VERSION 5.8 ;
BUSBITCHARS "[]" ;
DIVIDERCHAR "/" ;
UNITS
    DATABASE MICRONS 1000 ;
END UNITS

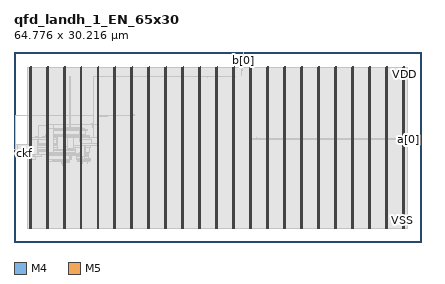
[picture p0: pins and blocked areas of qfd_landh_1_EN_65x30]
MACRO qfd_landh_1_EN_65x30
  FOREIGN qfd_landh_1_EN_65x30 0 0 ;
  CLASS BLOCK ;
  SIZE 64.776 BY 30.216 ;
  PIN a[0]
    DIRECTION INPUT ;
    USE SIGNAL ;
    PORT
      LAYER M4 ;
        RECT  64.692 16.272 64.776 16.296 ;
    END
  END a[0]
  PIN b[0]
    DIRECTION OUTPUT ;
    USE SIGNAL ;
    PORT
      LAYER M5 ;
        RECT  36.432 30.132 36.456 30.216 ;
    END
  END b[0]
  PIN ck
    DIRECTION INPUT ;
    USE SIGNAL ;
    PORT
      LAYER M4 ;
        RECT  0 13.968 0.084 13.992 ;
    END
  END ck
  PIN ckf
    DIRECTION INPUT ;
    USE SIGNAL ;
    PORT
      LAYER M4 ;
        RECT  0 14.064 0.084 14.088 ;
    END
  END ckf
  PIN ea
    DIRECTION INPUT ;
    USE SIGNAL ;
    PORT
      LAYER M4 ;
        RECT  64.692 16.368 64.776 16.392 ;
    END
  END ea
  PIN fault
    DIRECTION OUTPUT ;
    USE SIGNAL ;
    PORT
      LAYER M4 ;
        RECT  0 14.16 0.084 14.184 ;
    END
  END fault
  PIN k0
    DIRECTION INPUT ;
    USE SIGNAL ;
    PORT
      LAYER M4 ;
        RECT  0 14.256 0.084 14.28 ;
    END
  END k0
  PIN k1
    DIRECTION INPUT ;
    USE SIGNAL ;
    PORT
      LAYER M4 ;
        RECT  0 14.352 0.084 14.376 ;
    END
  END k1
  PIN k2
    DIRECTION INPUT ;
    USE SIGNAL ;
    PORT
      LAYER M4 ;
        RECT  0 14.448 0.084 14.472 ;
    END
  END k2
  PIN rs
    DIRECTION INPUT ;
    USE SIGNAL ;
    PORT
      LAYER M4 ;
        RECT  0 14.544 0.084 14.568 ;
    END
  END rs
  PIN tie_hi
    DIRECTION OUTPUT ;
    USE SIGNAL ;
    PORT
      LAYER M4 ;
        RECT  0 14.64 0.084 14.664 ;
    END
  END tie_hi
  PIN tie_lo
    DIRECTION OUTPUT ;
    USE SIGNAL ;
    PORT
      LAYER M4 ;
        RECT  0 14.736 0.084 14.76 ;
    END
  END tie_lo
  PIN VDD
    DIRECTION INOUT ;
    USE POWER ;
    PORT
      LAYER M5 ;
        RECT  61.992 2.151 62.112 27.833 ;
        RECT  59.292 2.151 59.412 27.833 ;
        RECT  56.592 2.151 56.712 27.833 ;
        RECT  53.892 2.151 54.012 27.833 ;
        RECT  51.192 2.151 51.312 27.833 ;
        RECT  48.492 2.151 48.612 27.833 ;
        RECT  45.792 2.151 45.912 27.833 ;
        RECT  43.092 2.151 43.212 27.833 ;
        RECT  40.392 2.151 40.512 27.833 ;
        RECT  37.692 2.151 37.812 27.833 ;
        RECT  34.992 2.151 35.112 27.833 ;
        RECT  32.292 2.151 32.412 27.833 ;
        RECT  29.592 2.151 29.712 27.833 ;
        RECT  26.892 2.151 27.012 27.833 ;
        RECT  24.192 2.151 24.312 27.833 ;
        RECT  21.492 2.151 21.612 27.833 ;
        RECT  18.792 2.151 18.912 27.833 ;
        RECT  16.092 2.151 16.212 27.833 ;
        RECT  13.392 2.151 13.512 27.833 ;
        RECT  10.692 2.151 10.812 27.833 ;
        RECT  7.992 2.151 8.112 27.833 ;
        RECT  5.292 2.151 5.412 27.833 ;
        RECT  2.592 2.151 2.712 27.833 ;
    END
  END VDD
  PIN VSS
    DIRECTION INOUT ;
    USE GROUND ;
    PORT
      LAYER M5 ;
        RECT  61.8 2.137 61.92 27.819 ;
        RECT  59.1 2.137 59.22 27.819 ;
        RECT  56.4 2.137 56.52 27.819 ;
        RECT  53.7 2.137 53.82 27.819 ;
        RECT  51 2.137 51.12 27.819 ;
        RECT  48.3 2.137 48.42 27.819 ;
        RECT  45.6 2.137 45.72 27.819 ;
        RECT  42.9 2.137 43.02 27.819 ;
        RECT  40.2 2.137 40.32 27.819 ;
        RECT  37.5 2.137 37.62 27.819 ;
        RECT  34.8 2.137 34.92 27.819 ;
        RECT  32.1 2.137 32.22 27.819 ;
        RECT  29.4 2.137 29.52 27.819 ;
        RECT  26.7 2.137 26.82 27.819 ;
        RECT  24 2.137 24.12 27.819 ;
        RECT  21.3 2.137 21.42 27.819 ;
        RECT  18.6 2.137 18.72 27.819 ;
        RECT  15.9 2.137 16.02 27.819 ;
        RECT  13.2 2.137 13.32 27.819 ;
        RECT  10.5 2.137 10.62 27.819 ;
        RECT  7.8 2.137 7.92 27.819 ;
        RECT  5.1 2.137 5.22 27.819 ;
        RECT  2.4 2.137 2.52 27.819 ;
    END
  END VSS
  OBS
    LAYER RVTN ;
     RECT  2.16 2.16 62.586 2.295 ;
     RECT  2.16 2.565 62.586 2.835 ;
     RECT  2.16 3.105 62.586 3.375 ;
     RECT  2.16 3.645 62.586 3.915 ;
     RECT  2.16 4.185 62.586 4.455 ;
     RECT  2.16 4.725 62.586 4.995 ;
     RECT  2.16 5.265 62.586 5.535 ;
     RECT  2.16 5.805 62.586 6.075 ;
     RECT  2.16 6.345 62.586 6.615 ;
     RECT  2.16 6.885 62.586 7.155 ;
     RECT  2.16 7.425 62.586 7.695 ;
     RECT  2.16 7.965 62.586 8.235 ;
     RECT  2.16 8.505 62.586 8.775 ;
     RECT  2.16 9.045 62.586 9.315 ;
     RECT  2.16 9.585 62.586 9.855 ;
     RECT  2.16 10.125 62.586 10.395 ;
     RECT  2.16 10.665 62.586 10.935 ;
     RECT  2.16 11.205 62.586 11.475 ;
     RECT  2.16 11.745 62.586 12.015 ;
     RECT  2.16 12.285 62.586 12.555 ;
     RECT  2.16 12.825 62.586 13.095 ;
     RECT  2.16 13.365 62.586 13.635 ;
     RECT  2.16 13.905 62.586 14.175 ;
     RECT  2.16 14.445 62.586 14.715 ;
     RECT  2.16 14.985 62.586 15.255 ;
     RECT  2.16 15.525 62.586 15.795 ;
     RECT  2.16 16.065 62.586 16.335 ;
     RECT  2.16 16.605 62.586 16.875 ;
     RECT  2.16 17.145 62.586 17.415 ;
     RECT  2.16 17.685 62.586 17.955 ;
     RECT  2.16 18.225 62.586 18.495 ;
     RECT  2.16 18.765 62.586 19.035 ;
     RECT  2.16 19.305 62.586 19.575 ;
     RECT  2.16 19.845 62.586 20.115 ;
     RECT  2.16 20.385 62.586 20.655 ;
     RECT  2.16 20.925 62.586 21.195 ;
     RECT  2.16 21.465 62.586 21.735 ;
     RECT  2.16 22.005 62.586 22.275 ;
     RECT  2.16 22.545 62.586 22.815 ;
     RECT  2.16 23.085 62.586 23.355 ;
     RECT  2.16 23.625 62.586 23.895 ;
     RECT  2.16 24.165 62.586 24.435 ;
     RECT  2.16 24.705 62.586 24.975 ;
     RECT  2.16 25.245 62.586 25.515 ;
     RECT  2.16 25.785 62.586 26.055 ;
     RECT  2.16 26.325 62.586 26.595 ;
     RECT  2.16 26.865 62.586 27.135 ;
     RECT  2.16 27.405 62.586 27.675 ;
    LAYER RVTP ;
     RECT  2.16 2.295 62.586 2.565 ;
     RECT  2.16 2.835 62.586 3.105 ;
     RECT  2.16 3.375 62.586 3.645 ;
     RECT  2.16 3.915 62.586 4.185 ;
     RECT  2.16 4.455 62.586 4.725 ;
     RECT  2.16 4.995 62.586 5.265 ;
     RECT  2.16 5.535 62.586 5.805 ;
     RECT  2.16 6.075 62.586 6.345 ;
     RECT  2.16 6.615 62.586 6.885 ;
     RECT  2.16 7.155 62.586 7.425 ;
     RECT  2.16 7.695 62.586 7.965 ;
     RECT  2.16 8.235 62.586 8.505 ;
     RECT  2.16 8.775 62.586 9.045 ;
     RECT  2.16 9.315 62.586 9.585 ;
     RECT  2.16 9.855 62.586 10.125 ;
     RECT  2.16 10.395 62.586 10.665 ;
     RECT  2.16 10.935 62.586 11.205 ;
     RECT  2.16 11.475 62.586 11.745 ;
     RECT  2.16 12.015 62.586 12.285 ;
     RECT  2.16 12.555 62.586 12.825 ;
     RECT  2.16 13.095 62.586 13.365 ;
     RECT  2.16 13.635 62.586 13.905 ;
     RECT  2.16 14.175 62.586 14.445 ;
     RECT  2.16 14.715 62.586 14.985 ;
     RECT  2.16 15.255 62.586 15.525 ;
     RECT  2.16 15.795 62.586 16.065 ;
     RECT  2.16 16.335 62.586 16.605 ;
     RECT  2.16 16.875 62.586 17.145 ;
     RECT  2.16 17.415 62.586 17.685 ;
     RECT  2.16 17.955 62.586 18.225 ;
     RECT  2.16 18.495 62.586 18.765 ;
     RECT  2.16 19.035 62.586 19.305 ;
     RECT  2.16 19.575 62.586 19.845 ;
     RECT  2.16 20.115 62.586 20.385 ;
     RECT  2.16 20.655 62.586 20.925 ;
     RECT  2.16 21.195 62.586 21.465 ;
     RECT  2.16 21.735 62.586 22.005 ;
     RECT  2.16 22.275 62.586 22.545 ;
     RECT  2.16 22.815 62.586 23.085 ;
     RECT  2.16 23.355 62.586 23.625 ;
     RECT  2.16 23.895 62.586 24.165 ;
     RECT  2.16 24.435 62.586 24.705 ;
     RECT  2.16 24.975 62.586 25.245 ;
     RECT  2.16 25.515 62.586 25.785 ;
     RECT  2.16 26.055 62.586 26.325 ;
     RECT  2.16 26.595 62.586 26.865 ;
     RECT  2.16 27.135 62.586 27.405 ;
     RECT  2.16 27.675 62.586 27.81 ;
    LAYER M1 ;
     RECT  2.16 2.151 62.586 27.819 ;
    LAYER M2 ;
     RECT  2.16 2.151 62.586 27.819 ;
     RECT  62.586 16.272 63.887 16.29 ;
    LAYER M3 ;
     RECT  2.415 2.143 2.505 2.413 ;
     RECT  5.115 2.143 5.205 2.413 ;
     RECT  7.815 2.143 7.905 2.413 ;
     RECT  10.515 2.143 10.605 2.413 ;
     RECT  13.215 2.143 13.305 2.413 ;
     RECT  15.915 2.143 16.005 2.413 ;
     RECT  18.615 2.143 18.705 2.413 ;
     RECT  21.315 2.143 21.405 2.413 ;
     RECT  24.015 2.143 24.105 2.413 ;
     RECT  26.715 2.143 26.805 2.413 ;
     RECT  29.415 2.143 29.505 2.413 ;
     RECT  32.115 2.143 32.205 2.413 ;
     RECT  34.815 2.143 34.905 2.413 ;
     RECT  37.515 2.143 37.605 2.413 ;
     RECT  40.215 2.143 40.305 2.413 ;
     RECT  42.915 2.143 43.005 2.413 ;
     RECT  45.615 2.143 45.705 2.413 ;
     RECT  48.315 2.143 48.405 2.413 ;
     RECT  51.015 2.143 51.105 2.413 ;
     RECT  53.715 2.143 53.805 2.413 ;
     RECT  56.415 2.143 56.505 2.413 ;
     RECT  59.115 2.143 59.205 2.413 ;
     RECT  61.815 2.143 61.905 2.413 ;
     RECT  7.815 2.413 8.097 12.181 ;
     RECT  7.668 12.181 8.097 12.361 ;
     RECT  7.668 12.361 8.154 12.451 ;
     RECT  7.596 12.451 8.226 12.523 ;
     RECT  10.515 2.413 10.797 12.559 ;
     RECT  7.596 12.523 8.262 12.631 ;
     RECT  7.596 12.631 8.874 12.757 ;
     RECT  10.515 12.559 10.854 12.757 ;
     RECT  11.7 12.559 11.718 12.757 ;
     RECT  10.188 12.757 12.006 12.793 ;
     RECT  6.12 12.811 6.138 12.901 ;
     RECT  6.984 12.757 8.874 12.901 ;
     RECT  10.152 12.793 12.006 12.901 ;
     RECT  6.12 12.901 8.874 13.051 ;
     RECT  5.115 2.413 5.397 13.099 ;
     RECT  6.12 13.051 8.946 13.099 ;
     RECT  10.152 12.901 12.15 13.099 ;
     RECT  2.415 2.413 2.697 13.171 ;
     RECT  5.115 13.099 8.946 13.171 ;
     RECT  10.044 13.099 12.15 13.171 ;
     RECT  10.008 13.171 12.15 13.325 ;
     RECT  10.008 13.325 11.862 13.531 ;
     RECT  4.32 13.531 4.338 13.639 ;
     RECT  2.415 13.171 3.402 13.675 ;
     RECT  4.176 13.639 4.338 13.675 ;
     RECT  5.115 13.171 9.162 13.711 ;
     RECT  9.9 13.531 11.862 13.711 ;
     RECT  2.415 13.675 4.338 13.837 ;
     RECT  5.115 13.711 11.862 13.837 ;
     RECT  2.415 13.837 11.862 13.945 ;
     RECT  2.34 13.945 11.862 14.135 ;
     RECT  2.34 14.135 9.738 14.215 ;
     RECT  10.476 14.135 11.862 14.243 ;
     RECT  10.515 14.243 11.862 14.251 ;
     RECT  0.432 14.251 0.45 14.347 ;
     RECT  0.36 14.347 0.45 14.429 ;
     RECT  0.36 14.429 0.378 14.443 ;
     RECT  0.144 14.443 0.378 14.477 ;
     RECT  2.304 14.215 9.738 14.573 ;
     RECT  2.34 14.573 9.738 14.669 ;
     RECT  0.144 14.477 0.162 14.717 ;
     RECT  2.415 14.669 9.738 15.025 ;
     RECT  10.515 14.251 12.042 15.025 ;
     RECT  2.415 15.025 12.186 15.331 ;
     RECT  13.215 2.413 13.497 15.331 ;
     RECT  2.415 15.331 13.497 15.593 ;
     RECT  63.864 16.261 63.882 16.301 ;
     RECT  2.415 15.593 12.294 16.331 ;
     RECT  38.664 16.231 38.682 16.363 ;
     RECT  14.868 16.267 14.886 16.367 ;
     RECT  38.52 16.363 38.682 16.529 ;
     RECT  38.52 16.529 38.538 16.565 ;
     RECT  2.415 16.331 11.97 16.673 ;
     RECT  3.42 16.673 11.97 16.685 ;
     RECT  3.42 16.685 3.726 16.799 ;
     RECT  4.464 16.685 11.97 16.799 ;
     RECT  4.68 16.799 11.97 16.835 ;
     RECT  5.004 16.835 11.97 16.943 ;
     RECT  5.004 16.943 11.358 17.117 ;
     RECT  5.115 17.117 11.358 17.761 ;
     RECT  5.115 17.761 11.646 17.879 ;
     RECT  7.308 17.879 11.214 18.023 ;
     RECT  5.115 17.879 6.426 18.029 ;
     RECT  5.115 18.029 5.886 18.059 ;
     RECT  13.215 15.593 13.497 18.121 ;
     RECT  7.308 18.023 10.926 18.149 ;
     RECT  7.308 18.149 8.91 18.185 ;
     RECT  9.792 18.149 10.926 18.221 ;
     RECT  12.708 18.121 13.497 18.265 ;
     RECT  5.115 18.059 5.49 18.701 ;
     RECT  12.528 18.265 13.497 18.763 ;
     RECT  12.276 18.763 13.497 18.797 ;
     RECT  12.276 18.797 12.294 18.803 ;
     RECT  14.832 19.963 14.85 20.189 ;
     RECT  18.615 2.413 18.897 20.191 ;
     RECT  18.615 20.191 19.206 20.285 ;
     RECT  8.892 18.185 8.91 26.249 ;
     RECT  34.815 2.413 35.097 26.257 ;
     RECT  34.815 26.257 35.262 26.333 ;
     RECT  30.78 26.221 30.798 26.393 ;
     RECT  36.144 26.401 36.162 27.059 ;
     RECT  36.252 27.211 36.27 27.301 ;
     RECT  36.252 27.301 36.414 27.365 ;
     RECT  2.415 16.673 2.697 27.557 ;
     RECT  5.115 18.701 5.397 27.557 ;
     RECT  7.815 18.185 8.097 27.557 ;
     RECT  10.515 18.221 10.797 27.557 ;
     RECT  13.215 18.797 13.497 27.557 ;
     RECT  15.915 2.413 16.197 27.557 ;
     RECT  18.615 20.285 18.897 27.557 ;
     RECT  21.315 2.413 21.597 27.557 ;
     RECT  24.015 2.413 24.297 27.557 ;
     RECT  26.715 2.413 26.997 27.557 ;
     RECT  29.415 2.413 29.697 27.557 ;
     RECT  32.115 2.413 32.397 27.557 ;
     RECT  34.815 26.333 35.097 27.557 ;
     RECT  37.515 2.413 37.797 27.557 ;
     RECT  40.215 2.413 40.497 27.557 ;
     RECT  42.915 2.413 43.197 27.557 ;
     RECT  45.615 2.413 45.897 27.557 ;
     RECT  48.315 2.413 48.597 27.557 ;
     RECT  51.015 2.413 51.297 27.557 ;
     RECT  53.715 2.413 53.997 27.557 ;
     RECT  56.415 2.413 56.697 27.557 ;
     RECT  59.115 2.413 59.397 27.557 ;
     RECT  61.815 2.413 62.097 27.557 ;
     RECT  2.607 27.557 2.697 27.827 ;
     RECT  5.307 27.557 5.397 27.827 ;
     RECT  8.007 27.557 8.097 27.827 ;
     RECT  10.707 27.557 10.797 27.827 ;
     RECT  13.407 27.557 13.497 27.827 ;
     RECT  16.107 27.557 16.197 27.827 ;
     RECT  18.807 27.557 18.897 27.827 ;
     RECT  21.507 27.557 21.597 27.827 ;
     RECT  24.207 27.557 24.297 27.827 ;
     RECT  26.907 27.557 26.997 27.827 ;
     RECT  29.607 27.557 29.697 27.827 ;
     RECT  32.307 27.557 32.397 27.827 ;
     RECT  35.007 27.557 35.097 27.827 ;
     RECT  37.707 27.557 37.797 27.827 ;
     RECT  40.407 27.557 40.497 27.827 ;
     RECT  43.107 27.557 43.197 27.827 ;
     RECT  45.807 27.557 45.897 27.827 ;
     RECT  48.507 27.557 48.597 27.827 ;
     RECT  51.207 27.557 51.297 27.827 ;
     RECT  53.907 27.557 53.997 27.827 ;
     RECT  56.607 27.557 56.697 27.827 ;
     RECT  59.307 27.557 59.397 27.827 ;
     RECT  62.007 27.557 62.097 27.827 ;
     RECT  36.396 27.365 36.414 29.693 ;
    LAYER M4 ;
     RECT  0.06 13.968 0.227 14.76 ;
     RECT  0.227 14.064 0.517 14.76 ;
     RECT  0.517 14.064 0.563 15.528 ;
     RECT  0.563 14.16 2.408 15.528 ;
     RECT  0.181 20.064 2.408 20.088 ;
     RECT  2.408 2.148 2.512 27.552 ;
     RECT  2.512 2.418 2.6 27.552 ;
     RECT  2.6 2.418 2.704 27.822 ;
     RECT  2.704 13.632 3.155 16.584 ;
     RECT  3.155 13.632 3.233 14.472 ;
     RECT  3.233 13.92 3.557 14.472 ;
     RECT  3.557 13.92 3.827 14.424 ;
     RECT  3.155 15.504 3.913 16.584 ;
     RECT  3.913 15.504 3.971 16.68 ;
     RECT  3.971 16.656 4.993 16.68 ;
     RECT  3.827 13.968 5.108 14.424 ;
     RECT  3.971 15.504 5.108 15.528 ;
     RECT  4.993 16.656 5.108 17.112 ;
     RECT  3.925 18.528 5.108 18.552 ;
     RECT  2.704 20.064 5.108 20.088 ;
     RECT  5.108 2.148 5.212 27.552 ;
     RECT  5.212 2.418 5.3 27.552 ;
     RECT  5.3 2.418 5.404 27.822 ;
     RECT  5.404 12.816 6.149 13.128 ;
     RECT  5.404 14.208 6.275 14.376 ;
     RECT  5.404 16.8 6.275 18.696 ;
     RECT  6.275 14.352 6.329 14.376 ;
     RECT  5.404 15.36 6.757 15.528 ;
     RECT  6.275 16.8 6.757 16.824 ;
     RECT  6.757 15.36 6.973 16.824 ;
     RECT  6.149 12.816 7.808 12.84 ;
     RECT  6.973 14.736 7.808 16.824 ;
     RECT  6.275 18 7.808 18.696 ;
     RECT  5.404 20.064 7.808 20.088 ;
     RECT  7.808 2.148 7.912 27.552 ;
     RECT  7.912 2.418 8 27.552 ;
     RECT  8 2.418 8.104 27.822 ;
     RECT  8.104 14.736 8.531 16.584 ;
     RECT  8.104 13.056 8.957 13.704 ;
     RECT  8.531 14.928 9.533 16.584 ;
     RECT  8.957 13.68 10.321 13.704 ;
     RECT  10.321 13.632 10.508 13.704 ;
     RECT  9.533 15.312 10.508 16.584 ;
     RECT  10.321 17.664 10.508 17.688 ;
     RECT  8.104 18.672 10.508 18.696 ;
     RECT  8.104 20.064 10.508 20.088 ;
     RECT  10.508 2.148 10.612 27.552 ;
     RECT  10.612 2.418 10.7 27.552 ;
     RECT  10.7 2.418 10.804 27.822 ;
     RECT  10.804 13.056 10.829 15.336 ;
     RECT  10.829 13.056 11.189 15.288 ;
     RECT  11.189 13.632 11.267 15.288 ;
     RECT  11.267 14.208 11.308 15.288 ;
     RECT  11.308 14.832 11.369 15.288 ;
     RECT  11.369 14.928 11.405 15.288 ;
     RECT  11.405 15.024 11.441 15.048 ;
     RECT  10.804 18.672 12.265 18.696 ;
     RECT  12.265 18.672 12.661 18.792 ;
     RECT  10.804 20.064 12.757 20.088 ;
     RECT  10.804 16.56 13.208 16.584 ;
     RECT  12.661 18.384 13.208 18.792 ;
     RECT  12.757 20.064 13.208 20.184 ;
     RECT  12.613 26.304 13.208 26.328 ;
     RECT  13.208 2.148 13.312 27.552 ;
     RECT  13.312 2.418 13.4 27.552 ;
     RECT  13.4 2.418 13.504 27.822 ;
     RECT  13.504 19.968 14.821 20.088 ;
     RECT  14.821 19.968 14.861 20.184 ;
     RECT  14.861 20.064 15.908 20.184 ;
     RECT  13.504 26.304 15.908 26.328 ;
     RECT  15.908 2.148 16.012 27.552 ;
     RECT  16.012 2.418 16.1 27.552 ;
     RECT  16.1 2.418 16.204 27.822 ;
     RECT  16.204 20.064 18.608 20.184 ;
     RECT  16.204 26.304 18.608 26.328 ;
     RECT  18.608 2.148 18.712 27.552 ;
     RECT  18.712 2.418 18.8 27.552 ;
     RECT  18.8 2.418 18.904 27.822 ;
     RECT  18.904 20.16 19.043 20.28 ;
     RECT  19.043 20.256 19.217 20.28 ;
     RECT  18.904 26.304 21.308 26.328 ;
     RECT  21.308 2.148 21.412 27.552 ;
     RECT  21.412 2.418 21.5 27.552 ;
     RECT  21.5 2.418 21.604 27.822 ;
     RECT  21.604 26.304 24.008 26.328 ;
     RECT  24.008 2.148 24.112 27.552 ;
     RECT  24.112 2.418 24.2 27.552 ;
     RECT  24.2 2.418 24.304 27.822 ;
     RECT  24.304 26.304 26.708 26.328 ;
     RECT  26.708 2.148 26.812 27.552 ;
     RECT  26.812 2.418 26.9 27.552 ;
     RECT  26.9 2.418 27.004 27.822 ;
     RECT  27.004 26.304 29.408 26.328 ;
     RECT  29.408 2.148 29.512 27.552 ;
     RECT  29.512 2.418 29.6 27.552 ;
     RECT  29.6 2.418 29.704 27.822 ;
     RECT  29.704 26.304 32.108 26.328 ;
     RECT  32.108 2.148 32.212 27.552 ;
     RECT  32.212 2.418 32.3 27.552 ;
     RECT  32.3 2.418 32.404 27.822 ;
     RECT  32.404 26.304 34.808 26.328 ;
     RECT  34.808 2.148 34.912 27.552 ;
     RECT  34.912 2.418 35 27.552 ;
     RECT  35 2.418 35.104 27.822 ;
     RECT  35.104 26.304 35.273 26.328 ;
     RECT  36.38 29.664 36.467 29.688 ;
     RECT  37.508 2.148 37.612 27.552 ;
     RECT  37.612 2.418 37.7 27.552 ;
     RECT  37.7 2.418 37.804 27.822 ;
     RECT  37.804 16.368 40.208 16.392 ;
     RECT  40.208 2.148 40.312 27.552 ;
     RECT  40.312 2.418 40.4 27.552 ;
     RECT  40.4 2.418 40.504 27.822 ;
     RECT  40.504 16.368 42.908 16.392 ;
     RECT  42.908 2.148 43.012 27.552 ;
     RECT  43.012 2.418 43.1 27.552 ;
     RECT  43.1 2.418 43.204 27.822 ;
     RECT  43.204 16.368 45.608 16.392 ;
     RECT  45.608 2.148 45.712 27.552 ;
     RECT  45.712 2.418 45.8 27.552 ;
     RECT  45.8 2.418 45.904 27.822 ;
     RECT  45.904 16.368 48.308 16.392 ;
     RECT  48.308 2.148 48.412 27.552 ;
     RECT  48.412 2.418 48.5 27.552 ;
     RECT  48.5 2.418 48.604 27.822 ;
     RECT  48.604 16.368 51.008 16.392 ;
     RECT  51.008 2.148 51.112 27.552 ;
     RECT  51.112 2.418 51.2 27.552 ;
     RECT  51.2 2.418 51.304 27.822 ;
     RECT  51.304 16.368 53.708 16.392 ;
     RECT  53.708 2.148 53.812 27.552 ;
     RECT  53.812 2.418 53.9 27.552 ;
     RECT  53.9 2.418 54.004 27.822 ;
     RECT  54.004 16.368 56.408 16.392 ;
     RECT  56.408 2.148 56.512 27.552 ;
     RECT  56.512 2.418 56.6 27.552 ;
     RECT  56.6 2.418 56.704 27.822 ;
     RECT  56.704 16.368 59.108 16.392 ;
     RECT  59.108 2.148 59.212 27.552 ;
     RECT  59.212 2.418 59.3 27.552 ;
     RECT  59.3 2.418 59.404 27.822 ;
     RECT  59.404 16.368 61.808 16.392 ;
     RECT  61.808 2.148 61.912 27.552 ;
     RECT  61.912 2.418 62 27.552 ;
     RECT  62 2.418 62.104 27.822 ;
     RECT  62.104 16.368 63.853 16.392 ;
     RECT  63.853 16.272 64.716 16.392 ;
    LAYER M5 ;
     RECT  2.4 2.137 2.52 2.151 ;
     RECT  5.1 2.137 5.22 2.151 ;
     RECT  7.8 2.137 7.92 2.151 ;
     RECT  10.5 2.137 10.62 2.151 ;
     RECT  13.2 2.137 13.32 2.151 ;
     RECT  15.9 2.137 16.02 2.151 ;
     RECT  18.6 2.137 18.72 2.151 ;
     RECT  21.3 2.137 21.42 2.151 ;
     RECT  24 2.137 24.12 2.151 ;
     RECT  26.7 2.137 26.82 2.151 ;
     RECT  29.4 2.137 29.52 2.151 ;
     RECT  32.1 2.137 32.22 2.151 ;
     RECT  34.8 2.137 34.92 2.151 ;
     RECT  37.5 2.137 37.62 2.151 ;
     RECT  40.2 2.137 40.32 2.151 ;
     RECT  42.9 2.137 43.02 2.151 ;
     RECT  45.6 2.137 45.72 2.151 ;
     RECT  48.3 2.137 48.42 2.151 ;
     RECT  51 2.137 51.12 2.151 ;
     RECT  53.7 2.137 53.82 2.151 ;
     RECT  56.4 2.137 56.52 2.151 ;
     RECT  59.1 2.137 59.22 2.151 ;
     RECT  61.8 2.137 61.92 2.151 ;
     RECT  7.8 2.151 8.112 13.045 ;
     RECT  2.4 2.151 2.712 13.621 ;
     RECT  10.5 2.151 10.812 13.621 ;
     RECT  7.8 13.045 8.904 13.715 ;
     RECT  2.4 13.621 3.144 13.909 ;
     RECT  0.192 13.957 0.216 14.053 ;
     RECT  5.1 2.151 5.412 14.197 ;
     RECT  7.8 13.715 8.112 14.725 ;
     RECT  7.8 14.725 8.52 15.155 ;
     RECT  10.5 13.621 11.256 15.299 ;
     RECT  0.192 14.053 0.552 15.539 ;
     RECT  7.8 15.155 8.232 15.539 ;
     RECT  10.5 15.299 10.812 15.973 ;
     RECT  2.4 13.909 3.816 16.357 ;
     RECT  13.2 2.151 13.512 16.549 ;
     RECT  2.4 16.357 3.96 16.595 ;
     RECT  10.368 15.973 10.812 17.699 ;
     RECT  5.1 14.197 6.264 18.035 ;
     RECT  3.936 16.595 3.96 18.563 ;
     RECT  12.672 16.549 13.512 18.661 ;
     RECT  0.192 15.539 0.216 20.099 ;
     RECT  18.6 2.151 18.912 20.149 ;
     RECT  18.6 20.149 19.032 20.291 ;
     RECT  12.624 18.661 13.512 26.339 ;
     RECT  2.4 16.595 2.712 27.819 ;
     RECT  5.1 18.035 5.412 27.819 ;
     RECT  7.8 15.539 8.112 27.819 ;
     RECT  10.5 17.699 10.812 27.819 ;
     RECT  13.2 26.339 13.512 27.819 ;
     RECT  15.9 2.151 16.212 27.819 ;
     RECT  18.6 20.291 18.912 27.819 ;
     RECT  21.3 2.151 21.612 27.819 ;
     RECT  24 2.151 24.312 27.819 ;
     RECT  26.7 2.151 27.012 27.819 ;
     RECT  29.4 2.151 29.712 27.819 ;
     RECT  32.1 2.151 32.412 27.819 ;
     RECT  34.8 2.151 35.112 27.819 ;
     RECT  37.5 2.151 37.812 27.819 ;
     RECT  40.2 2.151 40.512 27.819 ;
     RECT  42.9 2.151 43.212 27.819 ;
     RECT  45.6 2.151 45.912 27.819 ;
     RECT  48.3 2.151 48.612 27.819 ;
     RECT  51 2.151 51.312 27.819 ;
     RECT  53.7 2.151 54.012 27.819 ;
     RECT  56.4 2.151 56.712 27.819 ;
     RECT  59.1 2.151 59.412 27.819 ;
     RECT  61.8 2.151 62.112 27.819 ;
     RECT  2.592 27.819 2.712 27.833 ;
     RECT  5.292 27.819 5.412 27.833 ;
     RECT  7.992 27.819 8.112 27.833 ;
     RECT  10.692 27.819 10.812 27.833 ;
     RECT  13.392 27.819 13.512 27.833 ;
     RECT  16.092 27.819 16.212 27.833 ;
     RECT  18.792 27.819 18.912 27.833 ;
     RECT  21.492 27.819 21.612 27.833 ;
     RECT  24.192 27.819 24.312 27.833 ;
     RECT  26.892 27.819 27.012 27.833 ;
     RECT  29.592 27.819 29.712 27.833 ;
     RECT  32.292 27.819 32.412 27.833 ;
     RECT  34.992 27.819 35.112 27.833 ;
     RECT  37.692 27.819 37.812 27.833 ;
     RECT  40.392 27.819 40.512 27.833 ;
     RECT  43.092 27.819 43.212 27.833 ;
     RECT  45.792 27.819 45.912 27.833 ;
     RECT  48.492 27.819 48.612 27.833 ;
     RECT  51.192 27.819 51.312 27.833 ;
     RECT  53.892 27.819 54.012 27.833 ;
     RECT  56.592 27.819 56.712 27.833 ;
     RECT  59.292 27.819 59.412 27.833 ;
     RECT  61.992 27.819 62.112 27.833 ;
     RECT  36.432 29.653 36.456 30.16 ;
  END
END qfd_landh_1_EN_65x30
END LIBRARY
